One B-rep face of a CAD part: STEP entity #1682.
In plain terms, the planar face has unit normal (0, 1, 0).
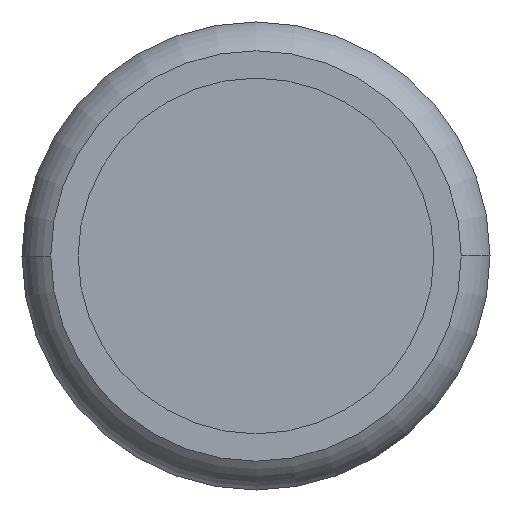
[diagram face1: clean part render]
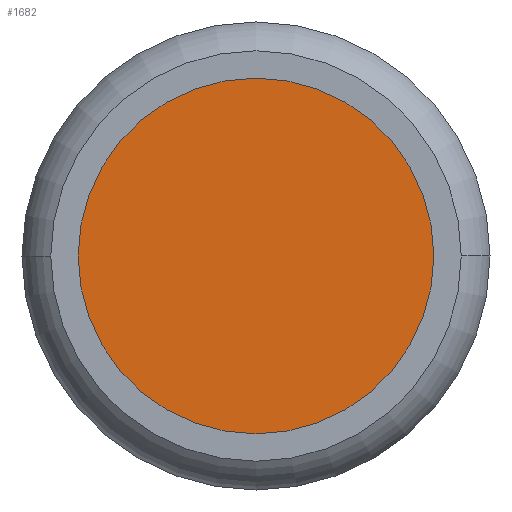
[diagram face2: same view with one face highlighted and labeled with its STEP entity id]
Its self-contained STEP definition (entity closure, numbers rounded to 3 decimals):
#533 = DIRECTION ( 'NONE',  ( 0., 0., -1. ) ) ;
#550 = DIRECTION ( 'NONE',  ( 0., -1., 0. ) ) ;
#564 = FACE_OUTER_BOUND ( 'NONE', #1879, .T. ) ;
#565 = CARTESIAN_POINT ( 'NONE',  ( -2.192, 2.45, 10. ) ) ;
#574 = PLANE ( 'NONE',  #6153 ) ;
#1682 = ADVANCED_FACE ( 'NONE', ( #564 ), #574, .F. ) ;
#1879 = EDGE_LOOP ( 'NONE', ( #6542, #6514 ) ) ;
#4410 = CARTESIAN_POINT ( 'NONE',  ( 0., 2.45, -1.9 ) ) ;
#4442 = CARTESIAN_POINT ( 'NONE',  ( 0., 2.45, 1.9 ) ) ;
#5710 = AXIS2_PLACEMENT_3D ( 'NONE', #7596, #7617, #7612 ) ;
#5711 = CIRCLE ( 'NONE', #5726, 1.9 ) ;
#5726 = AXIS2_PLACEMENT_3D ( 'NONE', #7624, #7619, #7620 ) ;
#5752 = CIRCLE ( 'NONE', #5710, 1.9 ) ;
#6153 = AXIS2_PLACEMENT_3D ( 'NONE', #565, #550, #533 ) ;
#6514 = ORIENTED_EDGE ( 'NONE', *, *, #7419, .F. ) ;
#6542 = ORIENTED_EDGE ( 'NONE', *, *, #7414, .F. ) ;
#6790 = VERTEX_POINT ( 'NONE', #4410 ) ;
#6834 = VERTEX_POINT ( 'NONE', #4442 ) ;
#7414 = EDGE_CURVE ( 'NONE', #6834, #6790, #5752, .T. ) ;
#7419 = EDGE_CURVE ( 'NONE', #6790, #6834, #5711, .T. ) ;
#7596 = CARTESIAN_POINT ( 'NONE',  ( 0., 2.45, 0. ) ) ;
#7612 = DIRECTION ( 'NONE',  ( 0., 0., -1. ) ) ;
#7617 = DIRECTION ( 'NONE',  ( 0., -1., 0. ) ) ;
#7619 = DIRECTION ( 'NONE',  ( 0., -1., 0. ) ) ;
#7620 = DIRECTION ( 'NONE',  ( 0., 0., -1. ) ) ;
#7624 = CARTESIAN_POINT ( 'NONE',  ( 0., 2.45, 0. ) ) ;
